VERSION 5.8 ;
BUSBITCHARS "[]" ;
DIVIDERCHAR "/" ;
UNITS
    DATABASE MICRONS 1000 ;
END UNITS

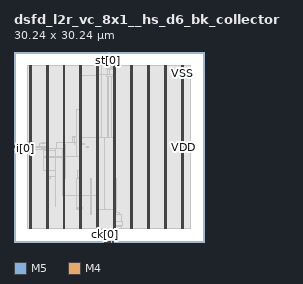
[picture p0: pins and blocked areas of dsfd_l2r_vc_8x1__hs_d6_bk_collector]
MACRO dsfd_l2r_vc_8x1__hs_d6_bk_collector
  FOREIGN dsfd_l2r_vc_8x1__hs_d6_bk_collector 0 0 ;
  CLASS BLOCK ;
  SIZE 30.24 BY 30.24 ;
  PIN ck[0]
    DIRECTION INPUT ;
    USE SIGNAL ;
    PORT
      LAYER M5 ;
        RECT  14.4 0 14.424 0.084 ;
    END
  END ck[0]
  PIN cks[0]
    DIRECTION INPUT ;
    USE SIGNAL ;
    PORT
      LAYER M5 ;
        RECT  14.592 0 14.616 0.084 ;
    END
  END cks[0]
  PIN fo[0]
    DIRECTION OUTPUT ;
    USE SIGNAL ;
    PORT
      LAYER M5 ;
        RECT  14.784 0 14.808 0.084 ;
    END
  END fo[0]
  PIN i[0]
    DIRECTION INPUT ;
    USE SIGNAL ;
    PORT
      LAYER M4 ;
        RECT  0 14.88 0.084 14.904 ;
    END
  END i[0]
  PIN i[1]
    DIRECTION INPUT ;
    USE SIGNAL ;
    PORT
      LAYER M4 ;
        RECT  0 14.928 0.084 14.952 ;
    END
  END i[1]
  PIN i[2]
    DIRECTION INPUT ;
    USE SIGNAL ;
    PORT
      LAYER M4 ;
        RECT  0 14.976 0.084 15 ;
    END
  END i[2]
  PIN i[3]
    DIRECTION INPUT ;
    USE SIGNAL ;
    PORT
      LAYER M4 ;
        RECT  0 15.024 0.084 15.048 ;
    END
  END i[3]
  PIN i[4]
    DIRECTION INPUT ;
    USE SIGNAL ;
    PORT
      LAYER M4 ;
        RECT  0 15.072 0.084 15.096 ;
    END
  END i[4]
  PIN i[5]
    DIRECTION INPUT ;
    USE SIGNAL ;
    PORT
      LAYER M4 ;
        RECT  0 15.12 0.084 15.144 ;
    END
  END i[5]
  PIN i[6]
    DIRECTION INPUT ;
    USE SIGNAL ;
    PORT
      LAYER M4 ;
        RECT  0 15.168 0.084 15.192 ;
    END
  END i[6]
  PIN i[7]
    DIRECTION INPUT ;
    USE SIGNAL ;
    PORT
      LAYER M4 ;
        RECT  0 15.216 0.084 15.24 ;
    END
  END i[7]
  PIN i[8]
    DIRECTION INPUT ;
    USE SIGNAL ;
    PORT
      LAYER M4 ;
        RECT  0 15.264 0.084 15.288 ;
    END
  END i[8]
  PIN od[0]
    DIRECTION OUTPUT ;
    USE SIGNAL ;
    PORT
      LAYER M5 ;
        RECT  14.976 0 15 0.084 ;
    END
  END od[0]
  PIN od[1]
    DIRECTION OUTPUT ;
    USE SIGNAL ;
    PORT
      LAYER M5 ;
        RECT  15.024 0 15.048 0.084 ;
    END
  END od[1]
  PIN od[2]
    DIRECTION OUTPUT ;
    USE SIGNAL ;
    PORT
      LAYER M5 ;
        RECT  15.072 0 15.096 0.084 ;
    END
  END od[2]
  PIN od[3]
    DIRECTION OUTPUT ;
    USE SIGNAL ;
    PORT
      LAYER M5 ;
        RECT  15.12 0 15.144 0.084 ;
    END
  END od[3]
  PIN od[4]
    DIRECTION OUTPUT ;
    USE SIGNAL ;
    PORT
      LAYER M5 ;
        RECT  15.168 0 15.192 0.084 ;
    END
  END od[4]
  PIN od[5]
    DIRECTION OUTPUT ;
    USE SIGNAL ;
    PORT
      LAYER M5 ;
        RECT  15.216 0 15.24 0.084 ;
    END
  END od[5]
  PIN od[6]
    DIRECTION OUTPUT ;
    USE SIGNAL ;
    PORT
      LAYER M5 ;
        RECT  15.264 0 15.288 0.084 ;
    END
  END od[6]
  PIN od[7]
    DIRECTION OUTPUT ;
    USE SIGNAL ;
    PORT
      LAYER M5 ;
        RECT  15.312 0 15.336 0.084 ;
    END
  END od[7]
  PIN od[8]
    DIRECTION OUTPUT ;
    USE SIGNAL ;
    PORT
      LAYER M5 ;
        RECT  15.36 0 15.384 0.084 ;
    END
  END od[8]
  PIN od[9]
    DIRECTION OUTPUT ;
    USE SIGNAL ;
    PORT
      LAYER M5 ;
        RECT  15.408 0 15.432 0.084 ;
    END
  END od[9]
  PIN rs[0]
    DIRECTION INPUT ;
    USE SIGNAL ;
    PORT
      LAYER M5 ;
        RECT  15.6 0 15.624 0.084 ;
    END
  END rs[0]
  PIN rss[0]
    DIRECTION INPUT ;
    USE SIGNAL ;
    PORT
      LAYER M5 ;
        RECT  15.792 0 15.816 0.084 ;
    END
  END rss[0]
  PIN st[0]
    DIRECTION OUTPUT ;
    USE SIGNAL ;
    PORT
      LAYER M5 ;
        RECT  15.024 30.156 15.048 30.24 ;
    END
  END st[0]
  PIN st[1]
    DIRECTION OUTPUT ;
    USE SIGNAL ;
    PORT
      LAYER M5 ;
        RECT  15.072 30.156 15.096 30.24 ;
    END
  END st[1]
  PIN st[2]
    DIRECTION OUTPUT ;
    USE SIGNAL ;
    PORT
      LAYER M5 ;
        RECT  15.12 30.156 15.144 30.24 ;
    END
  END st[2]
  PIN VDD
    DIRECTION INOUT ;
    USE POWER ;
    PORT
      LAYER M5 ;
        RECT  26.892 2.151 27.012 28.089 ;
        RECT  24.192 2.151 24.312 28.089 ;
        RECT  21.492 2.151 21.612 28.089 ;
        RECT  18.792 2.151 18.912 28.089 ;
        RECT  16.092 2.151 16.212 28.089 ;
        RECT  13.392 2.151 13.512 28.089 ;
        RECT  10.692 2.151 10.812 28.089 ;
        RECT  7.992 2.151 8.112 28.089 ;
        RECT  5.292 2.151 5.412 28.089 ;
        RECT  2.592 2.151 2.712 28.089 ;
    END
  END VDD
  PIN VSS
    DIRECTION INOUT ;
    USE GROUND ;
    PORT
      LAYER M5 ;
        RECT  26.7 2.137 26.82 28.103 ;
        RECT  24 2.137 24.12 28.103 ;
        RECT  21.3 2.137 21.42 28.103 ;
        RECT  18.6 2.137 18.72 28.103 ;
        RECT  15.9 2.137 16.02 28.103 ;
        RECT  13.2 2.137 13.32 28.103 ;
        RECT  10.5 2.137 10.62 28.103 ;
        RECT  7.8 2.137 7.92 28.103 ;
        RECT  5.1 2.137 5.22 28.103 ;
        RECT  2.4 2.137 2.52 28.103 ;
    END
  END VSS
  # OT_OBS_CLOSED layer=M5 d_um=1.536 added=2
  OBS
    LAYER RVTN ;
     RECT  2.16 2.16 28.08 2.295 ;
     RECT  2.16 2.565 28.08 2.835 ;
     RECT  2.16 3.105 28.08 3.375 ;
     RECT  2.16 3.645 28.08 3.915 ;
     RECT  2.16 4.185 28.08 4.455 ;
     RECT  2.16 4.725 28.08 4.995 ;
     RECT  2.16 5.265 28.08 5.535 ;
     RECT  2.16 5.805 28.08 6.075 ;
     RECT  2.16 6.345 28.08 6.615 ;
     RECT  2.16 6.885 28.08 7.155 ;
     RECT  2.16 7.425 28.08 7.695 ;
     RECT  2.16 7.965 28.08 8.235 ;
     RECT  2.16 8.505 28.08 8.775 ;
     RECT  2.16 9.045 28.08 9.315 ;
     RECT  2.16 9.585 28.08 9.855 ;
     RECT  2.16 10.125 28.08 10.395 ;
     RECT  2.16 10.665 28.08 10.935 ;
     RECT  2.16 11.205 28.08 11.475 ;
     RECT  2.16 11.745 28.08 12.015 ;
     RECT  2.16 12.285 28.08 12.555 ;
     RECT  2.16 12.825 28.08 13.095 ;
     RECT  2.16 13.365 28.08 13.635 ;
     RECT  2.16 13.905 28.08 14.175 ;
     RECT  2.16 14.445 28.08 14.715 ;
     RECT  2.16 14.985 28.08 15.255 ;
     RECT  2.16 15.525 28.08 15.795 ;
     RECT  2.16 16.065 28.08 16.335 ;
     RECT  2.16 16.605 28.08 16.875 ;
     RECT  2.16 17.145 28.08 17.415 ;
     RECT  2.16 17.685 28.08 17.955 ;
     RECT  2.16 18.225 28.08 18.495 ;
     RECT  2.16 18.765 28.08 19.035 ;
     RECT  2.16 19.305 28.08 19.575 ;
     RECT  2.16 19.845 28.08 20.115 ;
     RECT  2.16 20.385 28.08 20.655 ;
     RECT  2.16 20.925 28.08 21.195 ;
     RECT  2.16 21.465 28.08 21.735 ;
     RECT  2.16 22.005 28.08 22.275 ;
     RECT  2.16 22.545 28.08 22.815 ;
     RECT  2.16 23.085 28.08 23.355 ;
     RECT  2.16 23.625 28.08 23.895 ;
     RECT  2.16 24.165 28.08 24.435 ;
     RECT  2.16 24.705 28.08 24.975 ;
     RECT  2.16 25.245 28.08 25.515 ;
     RECT  2.16 25.785 28.08 26.055 ;
     RECT  2.16 26.325 28.08 26.595 ;
     RECT  2.16 26.865 28.08 27.135 ;
     RECT  2.16 27.405 28.08 27.675 ;
     RECT  2.16 27.945 28.08 28.08 ;
    LAYER RVTP ;
     RECT  2.16 2.295 28.08 2.565 ;
     RECT  2.16 2.835 28.08 3.105 ;
     RECT  2.16 3.375 28.08 3.645 ;
     RECT  2.16 3.915 28.08 4.185 ;
     RECT  2.16 4.455 28.08 4.725 ;
     RECT  2.16 4.995 28.08 5.265 ;
     RECT  2.16 5.535 28.08 5.805 ;
     RECT  2.16 6.075 28.08 6.345 ;
     RECT  2.16 6.615 28.08 6.885 ;
     RECT  2.16 7.155 28.08 7.425 ;
     RECT  2.16 7.695 28.08 7.965 ;
     RECT  2.16 8.235 28.08 8.505 ;
     RECT  2.16 8.775 28.08 9.045 ;
     RECT  2.16 9.315 28.08 9.585 ;
     RECT  2.16 9.855 28.08 10.125 ;
     RECT  2.16 10.395 28.08 10.665 ;
     RECT  2.16 10.935 28.08 11.205 ;
     RECT  2.16 11.475 28.08 11.745 ;
     RECT  2.16 12.015 28.08 12.285 ;
     RECT  2.16 12.555 28.08 12.825 ;
     RECT  2.16 13.095 28.08 13.365 ;
     RECT  2.16 13.635 28.08 13.905 ;
     RECT  2.16 14.175 28.08 14.445 ;
     RECT  2.16 14.715 28.08 14.985 ;
     RECT  2.16 15.255 28.08 15.525 ;
     RECT  2.16 15.795 28.08 16.065 ;
     RECT  2.16 16.335 28.08 16.605 ;
     RECT  2.16 16.875 28.08 17.145 ;
     RECT  2.16 17.415 28.08 17.685 ;
     RECT  2.16 17.955 28.08 18.225 ;
     RECT  2.16 18.495 28.08 18.765 ;
     RECT  2.16 19.035 28.08 19.305 ;
     RECT  2.16 19.575 28.08 19.845 ;
     RECT  2.16 20.115 28.08 20.385 ;
     RECT  2.16 20.655 28.08 20.925 ;
     RECT  2.16 21.195 28.08 21.465 ;
     RECT  2.16 21.735 28.08 22.005 ;
     RECT  2.16 22.275 28.08 22.545 ;
     RECT  2.16 22.815 28.08 23.085 ;
     RECT  2.16 23.355 28.08 23.625 ;
     RECT  2.16 23.895 28.08 24.165 ;
     RECT  2.16 24.435 28.08 24.705 ;
     RECT  2.16 24.975 28.08 25.245 ;
     RECT  2.16 25.515 28.08 25.785 ;
     RECT  2.16 26.055 28.08 26.325 ;
     RECT  2.16 26.595 28.08 26.865 ;
     RECT  2.16 27.135 28.08 27.405 ;
     RECT  2.16 27.675 28.08 27.945 ;
    LAYER M1 ;
     RECT  2.16 2.151 28.08 28.089 ;
    LAYER M2 ;
     RECT  0.139 14.76 0.211 14.778 ;
     RECT  0.211 14.688 2.16 14.778 ;
     RECT  2.16 2.151 13.423 28.089 ;
     RECT  13.423 2.034 13.999 28.089 ;
     RECT  13.999 1.998 14.855 28.089 ;
     RECT  14.855 2.034 15.467 28.089 ;
     RECT  15.467 2.151 28.08 28.089 ;
    LAYER M3 ;
     RECT  14.976 0.139 15.678 0.187 ;
     RECT  14.868 0.187 15.678 1.723 ;
     RECT  14.004 1.993 14.022 2.029 ;
     RECT  13.428 2.029 14.022 2.101 ;
     RECT  14.76 1.723 15.678 2.101 ;
     RECT  13.428 2.101 15.678 2.143 ;
     RECT  13.215 2.143 16.005 2.191 ;
     RECT  2.415 2.143 2.505 2.413 ;
     RECT  5.115 2.143 5.205 2.413 ;
     RECT  7.815 2.143 7.905 2.413 ;
     RECT  10.515 2.143 10.605 2.413 ;
     RECT  18.615 2.143 18.705 2.413 ;
     RECT  21.315 2.143 21.405 2.413 ;
     RECT  24.015 2.143 24.105 2.413 ;
     RECT  26.715 2.143 26.805 2.413 ;
     RECT  13.215 2.191 17.082 2.461 ;
     RECT  13.215 2.461 17.118 2.641 ;
     RECT  13.215 2.641 17.262 3.299 ;
     RECT  13.215 3.299 17.082 4.379 ;
     RECT  13.215 4.379 16.722 4.649 ;
     RECT  10.515 2.413 10.797 5.161 ;
     RECT  9.972 5.161 10.797 5.341 ;
     RECT  9.972 5.341 10.854 5.459 ;
     RECT  13.215 4.649 16.362 6.071 ;
     RECT  13.215 6.071 13.497 6.817 ;
     RECT  14.364 6.071 16.362 6.817 ;
     RECT  13.215 6.817 16.362 7.385 ;
     RECT  14.364 7.385 16.362 9.625 ;
     RECT  14.292 9.625 16.362 9.779 ;
     RECT  9.972 5.459 10.797 10.049 ;
     RECT  12.24 4.423 12.258 10.049 ;
     RECT  14.292 9.779 16.326 10.049 ;
     RECT  5.115 2.413 5.397 10.093 ;
     RECT  7.815 2.413 8.097 10.165 ;
     RECT  10.044 10.049 10.797 10.193 ;
     RECT  6.66 5.611 6.678 10.319 ;
     RECT  5.115 10.093 5.85 10.435 ;
     RECT  10.08 10.193 10.797 11.399 ;
     RECT  5.115 10.435 6.57 11.407 ;
     RECT  7.815 10.165 8.19 13.243 ;
     RECT  4.752 11.407 6.57 13.441 ;
     RECT  7.668 13.243 8.19 13.441 ;
     RECT  4.752 13.441 8.19 13.661 ;
     RECT  2.415 2.413 2.697 14.611 ;
     RECT  4.752 13.661 6.57 14.639 ;
     RECT  2.415 14.611 3.258 14.731 ;
     RECT  4.752 14.639 5.526 14.731 ;
     RECT  0.216 14.683 0.234 14.755 ;
     RECT  14.292 10.049 16.197 14.791 ;
     RECT  0.144 14.755 0.234 14.909 ;
     RECT  6.552 14.639 6.57 14.909 ;
     RECT  10.515 11.399 10.797 14.917 ;
     RECT  2.415 14.731 5.526 14.971 ;
     RECT  10.404 14.917 10.797 14.989 ;
     RECT  7.815 13.661 8.19 15.025 ;
     RECT  2.304 14.971 5.526 15.067 ;
     RECT  10.332 14.989 10.797 15.089 ;
     RECT  0.18 14.909 0.234 15.115 ;
     RECT  0.18 15.115 0.342 15.163 ;
     RECT  2.268 15.067 5.526 15.179 ;
     RECT  6.84 15.025 8.19 15.179 ;
     RECT  14.256 14.791 16.197 15.179 ;
     RECT  11.592 15.061 11.79 15.215 ;
     RECT  0.18 15.163 0.414 15.293 ;
     RECT  2.268 15.179 3.294 15.323 ;
     RECT  13.215 7.385 13.497 15.331 ;
     RECT  0.18 15.293 0.198 15.389 ;
     RECT  6.84 15.179 8.154 15.449 ;
     RECT  13.215 15.331 14.202 15.449 ;
     RECT  2.304 15.323 3.294 15.485 ;
     RECT  10.515 15.089 10.797 15.565 ;
     RECT  9.684 15.529 9.702 15.629 ;
     RECT  4.104 15.179 5.526 15.691 ;
     RECT  4.104 15.691 5.562 15.719 ;
     RECT  10.515 15.565 11.142 15.719 ;
     RECT  2.304 15.485 3.15 15.755 ;
     RECT  10.515 15.719 10.962 15.755 ;
     RECT  4.392 15.719 5.562 15.791 ;
     RECT  4.392 15.791 5.397 15.827 ;
     RECT  6.84 15.449 8.097 15.869 ;
     RECT  6.948 15.869 6.966 15.899 ;
     RECT  12.06 15.799 12.078 15.899 ;
     RECT  2.376 15.755 3.15 15.989 ;
     RECT  2.376 15.989 2.97 16.025 ;
     RECT  14.976 15.179 16.197 16.411 ;
     RECT  14.94 16.411 16.197 16.439 ;
     RECT  9.324 16.603 9.342 16.795 ;
     RECT  9.324 16.795 9.666 16.799 ;
     RECT  9.648 16.799 9.666 16.835 ;
     RECT  14.94 16.439 14.994 17.761 ;
     RECT  10.515 15.755 10.797 21.115 ;
     RECT  10.44 21.115 10.797 21.155 ;
     RECT  14.94 17.761 15.066 26.365 ;
     RECT  14.76 26.365 15.066 26.401 ;
     RECT  15.915 16.439 16.197 26.401 ;
     RECT  14.76 26.401 16.197 26.621 ;
     RECT  15.192 26.621 16.197 27.445 ;
     RECT  14.868 27.445 16.197 27.571 ;
     RECT  14.688 27.571 16.197 27.607 ;
     RECT  14.508 27.607 16.197 27.779 ;
     RECT  2.415 16.025 2.697 27.827 ;
     RECT  5.115 15.827 5.397 27.827 ;
     RECT  7.815 15.869 8.097 27.827 ;
     RECT  10.515 21.155 10.797 27.827 ;
     RECT  13.215 15.449 13.497 27.827 ;
     RECT  14.688 27.779 16.197 27.827 ;
     RECT  18.615 2.413 18.897 27.827 ;
     RECT  21.315 2.413 21.597 27.827 ;
     RECT  24.015 2.413 24.297 27.827 ;
     RECT  26.715 2.413 26.997 27.827 ;
     RECT  14.688 27.827 16.005 27.869 ;
     RECT  2.415 27.827 2.505 28.097 ;
     RECT  5.115 27.827 5.205 28.097 ;
     RECT  7.815 27.827 7.905 28.097 ;
     RECT  10.515 27.827 10.605 28.097 ;
     RECT  13.215 27.827 13.305 28.097 ;
     RECT  15.084 27.869 16.005 28.097 ;
     RECT  18.615 27.827 18.705 28.097 ;
     RECT  21.315 27.827 21.405 28.097 ;
     RECT  24.015 27.827 24.105 28.097 ;
     RECT  26.715 27.827 26.805 28.097 ;
     RECT  15.084 28.097 15.39 28.493 ;
     RECT  15.084 28.493 15.21 29.981 ;
     RECT  15.084 29.981 15.102 30.077 ;
    LAYER M4 ;
     RECT  0.06 14.88 0.133 15.288 ;
     RECT  0.133 14.88 0.169 15.336 ;
     RECT  0.169 14.88 0.173 15.384 ;
     RECT  0.173 14.928 0.245 15.384 ;
     RECT  0.245 14.976 2.408 15.384 ;
     RECT  2.408 2.148 2.512 28.092 ;
     RECT  2.512 2.418 2.704 27.822 ;
     RECT  2.704 15.216 3.305 15.288 ;
     RECT  3.805 14.736 4.417 14.76 ;
     RECT  4.417 14.736 5.108 14.856 ;
     RECT  5.108 2.148 5.212 28.092 ;
     RECT  5.212 2.418 5.404 27.822 ;
     RECT  5.404 14.88 6.829 14.904 ;
     RECT  7.261 13.632 7.628 13.656 ;
     RECT  7.669 7.344 7.808 7.368 ;
     RECT  7.628 13.248 7.808 13.656 ;
     RECT  6.829 14.88 7.808 15.864 ;
     RECT  7.808 2.148 7.912 28.092 ;
     RECT  7.912 2.418 8.104 27.822 ;
     RECT  8.104 15.84 9.313 15.864 ;
     RECT  9.313 15.84 9.637 16.632 ;
     RECT  9.925 21.12 10.357 21.144 ;
     RECT  8.104 7.344 10.508 7.368 ;
     RECT  8.104 13.632 10.508 13.656 ;
     RECT  9.637 15.84 10.508 16.824 ;
     RECT  10.357 21.12 10.508 21.24 ;
     RECT  10.357 26.352 10.508 26.376 ;
     RECT  10.508 2.148 10.612 28.092 ;
     RECT  10.612 2.418 10.804 27.822 ;
     RECT  10.804 26.496 13.093 26.52 ;
     RECT  10.804 7.344 13.208 7.368 ;
     RECT  10.804 16.608 13.208 16.632 ;
     RECT  13.093 26.496 13.208 26.616 ;
     RECT  13.208 2.148 13.312 28.092 ;
     RECT  13.312 2.418 13.504 27.822 ;
     RECT  13.504 7.344 14.141 7.368 ;
     RECT  13.504 16.608 14.435 16.632 ;
     RECT  13.504 3.6 14.581 3.624 ;
     RECT  14.533 2.256 14.732 2.28 ;
     RECT  14.497 5.664 14.749 5.688 ;
     RECT  13.504 26.592 14.789 26.616 ;
     RECT  14.749 5.136 14.861 5.688 ;
     RECT  14.857 0.192 14.893 0.216 ;
     RECT  14.893 0.192 14.965 0.552 ;
     RECT  14.965 0.144 15.001 0.552 ;
     RECT  15.001 0.144 15.109 0.6 ;
     RECT  14.732 1.728 15.109 2.28 ;
     RECT  14.581 3.6 15.109 4.008 ;
     RECT  15.029 30.048 15.109 30.072 ;
     RECT  15.109 29.952 15.113 30.072 ;
     RECT  15.109 0.144 15.193 4.008 ;
     RECT  15.113 29.952 15.221 29.976 ;
     RECT  15.193 1.728 15.349 4.008 ;
     RECT  14.861 5.136 15.349 5.256 ;
     RECT  15.349 1.728 15.365 5.256 ;
     RECT  15.365 1.824 15.401 5.256 ;
     RECT  15.013 28.464 15.401 28.488 ;
     RECT  15.193 0.144 15.635 0.552 ;
     RECT  15.635 0.144 15.689 0.504 ;
     RECT  15.689 0.48 15.827 0.504 ;
     RECT  15.401 2.148 15.908 5.256 ;
     RECT  15.908 2.148 16.012 28.092 ;
     RECT  16.012 2.418 16.204 27.822 ;
     RECT  16.204 5.232 16.265 5.256 ;
     RECT  18.608 2.148 18.712 28.092 ;
     RECT  18.712 2.418 18.904 27.822 ;
     RECT  21.308 2.148 21.412 28.092 ;
     RECT  21.412 2.418 21.604 27.822 ;
     RECT  24.008 2.148 24.112 28.092 ;
     RECT  24.112 2.418 24.304 27.822 ;
     RECT  26.708 2.148 26.812 28.092 ;
     RECT  26.812 2.418 27.004 27.822 ;
    LAYER M5 ;
     RECT  14.4 0.016 15.816 0.515 ;
     RECT  14.4 0.515 15.624 0.563 ;
     RECT  14.4 0.563 15.384 2.137 ;
     RECT  2.4 2.137 2.52 2.151 ;
     RECT  5.1 2.137 5.22 2.151 ;
     RECT  7.8 2.137 7.92 2.151 ;
     RECT  10.5 2.137 10.62 2.151 ;
     RECT  13.2 2.137 13.32 2.151 ;
     RECT  14.4 2.137 16.02 2.151 ;
     RECT  18.6 2.137 18.72 2.151 ;
     RECT  21.3 2.137 21.42 2.151 ;
     RECT  24 2.137 24.12 2.151 ;
     RECT  26.7 2.137 26.82 2.151 ;
     RECT  13.2 2.151 16.212 5.171 ;
     RECT  7.8 2.151 8.112 7.333 ;
     RECT  10.5 2.151 10.812 13.621 ;
     RECT  7.68 7.333 8.112 14.915 ;
     RECT  0.144 15.205 0.168 15.347 ;
     RECT  13.2 5.171 14.424 16.643 ;
     RECT  9.936 13.621 10.812 21.155 ;
     RECT  10.368 21.155 10.812 26.387 ;
     RECT  13.2 16.643 13.512 26.485 ;
     RECT  13.104 26.485 13.512 26.627 ;
     RECT  2.4 2.151 2.712 28.089 ;
     RECT  5.1 2.151 5.412 28.089 ;
     RECT  7.8 14.915 8.112 28.089 ;
     RECT  10.5 26.387 10.812 28.089 ;
     RECT  13.2 26.627 13.512 28.089 ;
     RECT  15.9 5.171 16.212 28.089 ;
     RECT  18.6 2.151 18.912 28.089 ;
     RECT  21.3 2.151 21.612 28.089 ;
     RECT  24 2.151 24.312 28.089 ;
     RECT  26.7 2.151 27.012 28.089 ;
     RECT  2.4 28.089 2.52 28.103 ;
     RECT  5.1 28.089 5.22 28.103 ;
     RECT  7.8 28.089 7.92 28.103 ;
     RECT  10.5 28.089 10.62 28.103 ;
     RECT  13.2 28.089 13.32 28.103 ;
     RECT  15.9 28.089 16.02 28.103 ;
     RECT  18.6 28.089 18.72 28.103 ;
     RECT  21.3 28.089 21.42 28.103 ;
     RECT  24 28.089 24.12 28.103 ;
     RECT  26.7 28.089 26.82 28.103 ;
     RECT  15.024 28.453 15.048 29.941 ;
     RECT  15.024 29.941 15.144 30.224 ;
     RECT  13.32 2.137 14.4 2.151 ;
     RECT  14.424 5.171 15.9 16.643 ;
  END
END dsfd_l2r_vc_8x1__hs_d6_bk_collector
END LIBRARY
